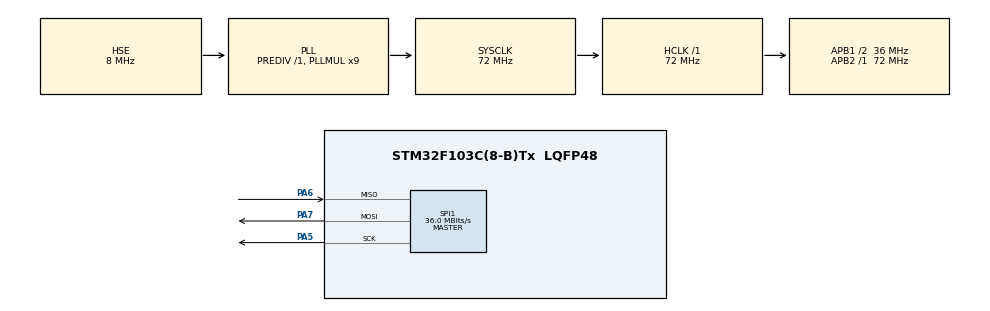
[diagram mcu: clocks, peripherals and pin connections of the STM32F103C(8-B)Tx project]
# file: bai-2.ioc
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Mcu.Family=STM32F1
Mcu.Name=STM32F103C(8-B)Tx
Mcu.Package=LQFP48
NVIC.PriorityGroup=NVIC_PRIORITYGROUP_4
PA5.Mode=Full_Duplex_Master
PA5.Signal=SPI1_SCK
PA6.Mode=Full_Duplex_Master
PA6.Signal=SPI1_MISO
PA7.Mode=Full_Duplex_Master
PA7.Signal=SPI1_MOSI
PD0-OSC_IN.Mode=HSE-External-Oscillator
PD0-OSC_IN.Signal=RCC_OSC_IN
PD1-OSC_OUT.Mode=HSE-External-Oscillator
PD1-OSC_OUT.Signal=RCC_OSC_OUT
ProjectManager.HeapSize=0x200
ProjectManager.StackSize=0x400
ProjectManager.TargetToolchain=Makefile
RCC.AHBFreq_Value=72000000
RCC.APB1CLKDivider=RCC_HCLK_DIV2
RCC.APB1Freq_Value=36000000
RCC.APB1TimFreq_Value=72000000
RCC.APB2Freq_Value=72000000
RCC.APB2TimFreq_Value=72000000
RCC.HCLKFreq_Value=72000000
RCC.PLLMUL=RCC_PLL_MUL9
RCC.PLLSourceVirtual=RCC_PLLSOURCE_HSE
RCC.SYSCLKFreq_VALUE=72000000
RCC.SYSCLKSource=RCC_SYSCLKSOURCE_PLLCLK
RCC.USBFreq_Value=72000000
SPI1.BaudRatePrescaler=SPI_BAUDRATEPRESCALER_2
SPI1.CalculateBaudRate=36.0 MBits/s
SPI1.Direction=SPI_DIRECTION_2LINES
SPI1.Mode=SPI_MODE_MASTER
SPI1.VirtualType=VM_MASTER
VP_SYS_VS_ND.Mode=No_Debug
board=custom

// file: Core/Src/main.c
/* USER CODE BEGIN Header */
/**
  ******************************************************************************
  * @file           : main.c
  * @brief          : Main program body
  ******************************************************************************
  * @attention
  *
  * Copyright (c) 2026 STMicroelectronics.
  * All rights reserved.
  *
  * This software is licensed under terms that can be found in the LICENSE file
  * in the root directory of this software component.
  * If no LICENSE file comes with this software, it is provided AS-IS.
  *
  ******************************************************************************
  */
/* USER CODE END Header */
#include "main.h"

/* USER CODE BEGIN Includes */
#include "ST7735.h"

/* USER CODE END Includes */

SPI_HandleTypeDef hspi1;

void SystemClock_Config(void);
static void MX_GPIO_Init(void);
static void MX_SPI1_Init(void);

int main(void)
{

  /* MCU Configuration--------------------------------------------------------*/

  /* Reset of all peripherals, Initializes the Flash interface and the Systick. */
  HAL_Init();

  /* Configure the system clock */
  SystemClock_Config();

  /* Initialize all configured peripherals */
  MX_GPIO_Init();
  MX_SPI1_Init();
  /* USER CODE BEGIN 2 */
  ST7735_Init();
  ST7735_FillScreen(BLACK);

  ST7735_DrawString(
      10, 20,
      "HNhom 7",
      WHITE,
      BLACK,
      FONT_SIZE_2
  );

  HAL_Delay(1000);
   ST7735_FillScreen(BLACK);
  ST7735_DrawString(
      40, 20,
      "Cout",
      WHITE,
      BLACK,
      FONT_SIZE_2
  );
  int16_t x = 0;
  /* USER CODE END 2 */

  /* Infinite loop */
  /* USER CODE BEGIN WHILE */
  while (1)
  {
    ST7735_DrawInt(
      50, 60,
      x,
      YELLOW,
      BLACK,
      FONT_SIZE_3
    );
    x++;
    if(x > 60)
    {
      x = 0;
    }
    HAL_Delay(1000);
    /* USER CODE END WHILE */

  }
}

void SystemClock_Config(void)
{
  RCC_OscInitTypeDef RCC_OscInitStruct = {0};
  RCC_ClkInitTypeDef RCC_ClkInitStruct = {0};

  /** Initializes the RCC Oscillators according to the specified parameters
  * in the RCC_OscInitTypeDef structure.
  */
  RCC_OscInitStruct.OscillatorType = RCC_OSCILLATORTYPE_HSE;
  RCC_OscInitStruct.HSEState = RCC_HSE_ON;
  RCC_OscInitStruct.HSEPredivValue = RCC_HSE_PREDIV_DIV1;
  RCC_OscInitStruct.HSIState = RCC_HSI_ON;
  RCC_OscInitStruct.PLL.PLLState = RCC_PLL_ON;
  RCC_OscInitStruct.PLL.PLLSource = RCC_PLLSOURCE_HSE;
  RCC_OscInitStruct.PLL.PLLMUL = RCC_PLL_MUL9;
  if (HAL_RCC_OscConfig(&RCC_OscInitStruct) != HAL_OK)
  {
    Error_Handler();
  }

  /** Initializes the CPU, AHB and APB buses clocks
  */
  RCC_ClkInitStruct.ClockType = RCC_CLOCKTYPE_HCLK|RCC_CLOCKTYPE_SYSCLK
                              |RCC_CLOCKTYPE_PCLK1|RCC_CLOCKTYPE_PCLK2;
  RCC_ClkInitStruct.SYSCLKSource = RCC_SYSCLKSOURCE_PLLCLK;
  RCC_ClkInitStruct.AHBCLKDivider = RCC_SYSCLK_DIV1;
  RCC_ClkInitStruct.APB1CLKDivider = RCC_HCLK_DIV2;
  RCC_ClkInitStruct.APB2CLKDivider = RCC_HCLK_DIV1;

  if (HAL_RCC_ClockConfig(&RCC_ClkInitStruct, FLASH_LATENCY_2) != HAL_OK)
  {
    Error_Handler();
  }
}

static void MX_SPI1_Init(void)
{

  /* SPI1 parameter configuration*/
  hspi1.Instance = SPI1;
  hspi1.Init.Mode = SPI_MODE_MASTER;
  hspi1.Init.Direction = SPI_DIRECTION_2LINES;
  hspi1.Init.DataSize = SPI_DATASIZE_8BIT;
  hspi1.Init.CLKPolarity = SPI_POLARITY_LOW;
  hspi1.Init.CLKPhase = SPI_PHASE_1EDGE;
  hspi1.Init.NSS = SPI_NSS_SOFT;
  hspi1.Init.BaudRatePrescaler = SPI_BAUDRATEPRESCALER_2;
  hspi1.Init.FirstBit = SPI_FIRSTBIT_MSB;
  hspi1.Init.TIMode = SPI_TIMODE_DISABLE;
  hspi1.Init.CRCCalculation = SPI_CRCCALCULATION_DISABLE;
  hspi1.Init.CRCPolynomial = 10;
  if (HAL_SPI_Init(&hspi1) != HAL_OK)
  {
    Error_Handler();
  }

}

static void MX_GPIO_Init(void)
{

  /* GPIO Ports Clock Enable */
  __HAL_RCC_GPIOD_CLK_ENABLE();
  __HAL_RCC_GPIOA_CLK_ENABLE();
  __HAL_RCC_GPIOB_CLK_ENABLE();

  GPIO_InitTypeDef GPIO_InitStruct = {0};

  HAL_GPIO_WritePin(GPIOB, GPIO_PIN_6|GPIO_PIN_7|GPIO_PIN_8|GPIO_PIN_9,
                    GPIO_PIN_SET);
  GPIO_InitStruct.Pin = GPIO_PIN_6|GPIO_PIN_7|GPIO_PIN_8|GPIO_PIN_9;
  GPIO_InitStruct.Mode = GPIO_MODE_OUTPUT_PP;
  GPIO_InitStruct.Pull = GPIO_NOPULL;
  GPIO_InitStruct.Speed = GPIO_SPEED_FREQ_HIGH;
  HAL_GPIO_Init(GPIOB, &GPIO_InitStruct);

}

void Error_Handler(void)
{
  __disable_irq();
  while (1)
  {
  }
}
